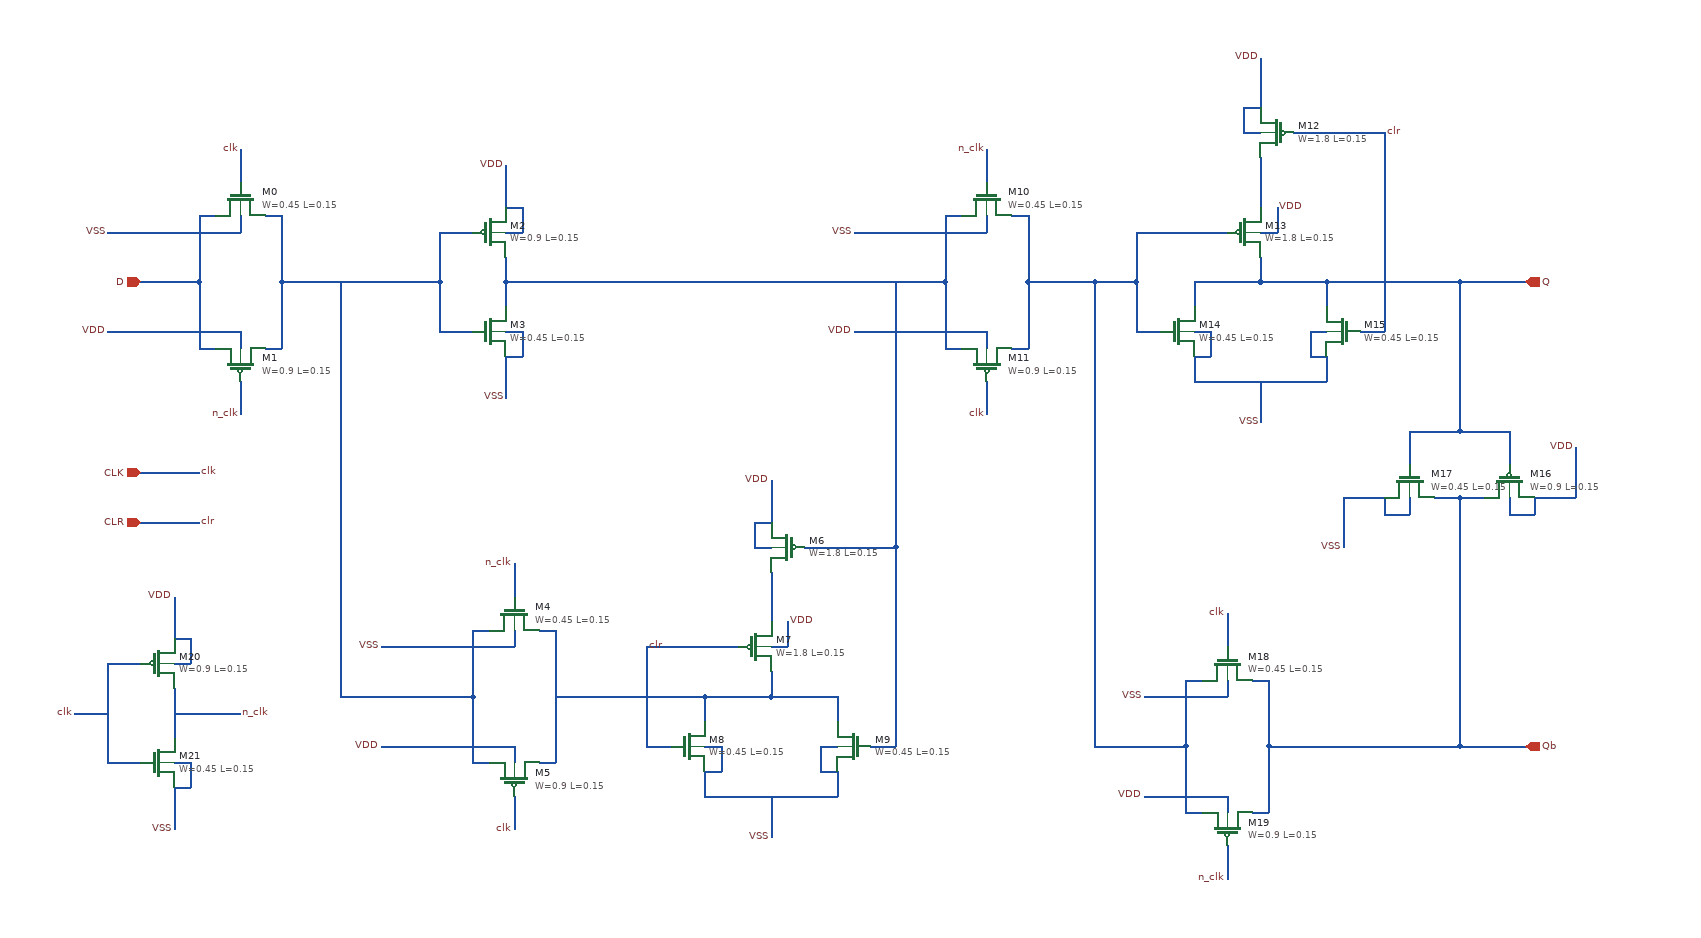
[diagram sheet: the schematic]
v {xschem version=2.9.9 file_version=1.2 }
G {}
K {}
V {}
S {}
E {}
N -3450 -1260 -3420 -1260 { lab=VDD}
N -3420 -1260 -3420 -1240 { lab=VDD}
N -3420 -1400 -3420 -1380 { lab=VSS}
N -3450 -1380 -3420 -1380 { lab=VSS}
N -3420 -1200 -3420 -1160 { lab=n_clk}
N -3420 -1480 -3420 -1440 { lab=clk}
N -3470 -1400 -3450 -1400 { lab=D}
N -3470 -1320 -3470 -1240 { lab=D}
N -3470 -1240 -3450 -1240 { lab=D}
N -3390 -1240 -3370 -1240 { lab=#net1}
N -3370 -1320 -3370 -1240 { lab=#net1}
N -3390 -1400 -3370 -1400 { lab=#net1}
N -3540 -1320 -3470 -1320 { lab=D}
N -3180 -1380 -3140 -1380 { lab=#net1}
N -3180 -1320 -3180 -1260 { lab=#net1}
N -3180 -1260 -3140 -1260 { lab=#net1}
N -3100 -1260 -3080 -1260 { lab=VSS}
N -3080 -1260 -3080 -1230 { lab=VSS}
N -3100 -1230 -3080 -1230 { lab=VSS}
N -3100 -1410 -3080 -1410 { lab=VDD}
N -3080 -1410 -3080 -1380 { lab=VDD}
N -3100 -1380 -3080 -1380 { lab=VDD}
N -3100 -1230 -3100 -1180 { lab=VSS}
N -3100 -1460 -3100 -1410 { lab=VDD}
N -3100 -1320 -3100 -1290 { lab=#net2}
N -3120 -760 -3090 -760 { lab=VDD}
N -3090 -760 -3090 -740 { lab=VDD}
N -3090 -900 -3090 -880 { lab=VSS}
N -3120 -880 -3090 -880 { lab=VSS}
N -3090 -700 -3090 -660 { lab=clk}
N -3090 -980 -3090 -940 { lab=n_clk}
N -3140 -900 -3120 -900 { lab=#net1}
N -3140 -820 -3140 -740 { lab=#net1}
N -3140 -740 -3120 -740 { lab=#net1}
N -3060 -740 -3040 -740 { lab=#net3}
N -3040 -900 -3040 -740 { lab=#net3}
N -3060 -900 -3040 -900 { lab=#net3}
N -3210 -820 -3140 -820 { lab=#net1}
N -2780 -970 -2780 -910 { lab=#net4}
N -2800 -1030 -2780 -1030 { lab=VDD}
N -2800 -1030 -2800 -1000 { lab=VDD}
N -2800 -1000 -2780 -1000 { lab=VDD}
N -2780 -880 -2760 -880 { lab=VDD}
N -2760 -910 -2760 -880 { lab=VDD}
N -2860 -760 -2840 -760 { lab=VSS}
N -2840 -760 -2840 -730 { lab=VSS}
N -2860 -730 -2840 -730 { lab=VSS}
N -2720 -760 -2700 -760 { lab=VSS}
N -2720 -760 -2720 -730 { lab=VSS}
N -2720 -730 -2700 -730 { lab=VSS}
N -2860 -730 -2860 -700 { lab=VSS}
N -2860 -700 -2700 -700 { lab=VSS}
N -2700 -730 -2700 -700 { lab=VSS}
N -2860 -820 -2860 -790 { lab=#net3}
N -2780 -820 -2700 -820 { lab=#net3}
N -2700 -820 -2700 -790 { lab=#net3}
N -2780 -850 -2780 -820 { lab=#net3}
N -2930 -760 -2900 -760 { lab=clr}
N -2930 -880 -2930 -760 { lab=clr}
N -2930 -880 -2820 -880 { lab=clr}
N -2660 -760 -2630 -760 { lab=#net2}
N -2630 -1000 -2630 -760 { lab=#net2}
N -2740 -1000 -2630 -1000 { lab=#net2}
N -2550 -1260 -2520 -1260 { lab=VDD}
N -2520 -1260 -2520 -1240 { lab=VDD}
N -2520 -1400 -2520 -1380 { lab=VSS}
N -2550 -1380 -2520 -1380 { lab=VSS}
N -2520 -1200 -2520 -1160 { lab=clk}
N -2520 -1480 -2520 -1440 { lab=n_clk}
N -2570 -1400 -2550 -1400 { lab=#net2}
N -2570 -1320 -2570 -1240 { lab=#net2}
N -2570 -1240 -2550 -1240 { lab=#net2}
N -2490 -1240 -2470 -1240 { lab=#net5}
N -2470 -1320 -2470 -1240 { lab=#net5}
N -2490 -1400 -2470 -1400 { lab=#net5}
N -2190 -1470 -2190 -1410 { lab=#net6}
N -2210 -1530 -2190 -1530 { lab=VDD}
N -2210 -1530 -2210 -1500 { lab=VDD}
N -2210 -1500 -2190 -1500 { lab=VDD}
N -2190 -1380 -2170 -1380 { lab=VDD}
N -2170 -1410 -2170 -1380 { lab=VDD}
N -2270 -1260 -2250 -1260 { lab=VSS}
N -2250 -1260 -2250 -1230 { lab=VSS}
N -2270 -1230 -2250 -1230 { lab=VSS}
N -2130 -1260 -2110 -1260 { lab=VSS}
N -2130 -1260 -2130 -1230 { lab=VSS}
N -2130 -1230 -2110 -1230 { lab=VSS}
N -2270 -1230 -2270 -1200 { lab=VSS}
N -2270 -1200 -2110 -1200 { lab=VSS}
N -2110 -1230 -2110 -1200 { lab=VSS}
N -2270 -1320 -2270 -1290 { lab=Q}
N -2190 -1320 -2110 -1320 { lab=Q}
N -2110 -1320 -2110 -1290 { lab=Q}
N -2190 -1350 -2190 -1320 { lab=Q}
N -2340 -1260 -2310 -1260 { lab=#net5}
N -2340 -1320 -2340 -1260 { lab=#net5}
N -2340 -1380 -2230 -1380 { lab=#net5}
N -2070 -1260 -2040 -1260 { lab=clr}
N -2040 -1500 -2040 -1260 { lab=clr}
N -2150 -1500 -2040 -1500 { lab=clr}
N -1890 -1140 -1890 -1100 { lab=Q}
N -1950 -1140 -1890 -1140 { lab=Q}
N -2010 -1140 -2010 -1100 { lab=Q}
N -2010 -1060 -2010 -1040 { lab=VSS}
N -2040 -1040 -2010 -1040 { lab=VSS}
N -2040 -1060 -2040 -1040 { lab=VSS}
N -1860 -1060 -1860 -1040 { lab=VDD}
N -1890 -1040 -1860 -1040 { lab=VDD}
N -1890 -1060 -1890 -1040 { lab=VDD}
N -2090 -1060 -2040 -1060 { lab=VSS}
N -1860 -1060 -1810 -1060 { lab=VDD}
N -1950 -1060 -1920 -1060 { lab=Qb}
N -2260 -700 -2230 -700 { lab=VDD}
N -2230 -700 -2230 -680 { lab=VDD}
N -2230 -840 -2230 -820 { lab=VSS}
N -2260 -820 -2230 -820 { lab=VSS}
N -2230 -640 -2230 -600 { lab=n_clk}
N -2230 -920 -2230 -880 { lab=clk}
N -2280 -840 -2260 -840 { lab=#net5}
N -2280 -760 -2280 -680 { lab=#net5}
N -2280 -680 -2260 -680 { lab=#net5}
N -2200 -680 -2180 -680 { lab=Qb}
N -2180 -760 -2180 -680 { lab=Qb}
N -2200 -840 -2180 -840 { lab=Qb}
N -3580 -860 -3540 -860 { lab=clk}
N -3580 -860 -3580 -740 { lab=clk}
N -3580 -740 -3540 -740 { lab=clk}
N -3500 -740 -3480 -740 { lab=VSS}
N -3480 -740 -3480 -710 { lab=VSS}
N -3500 -710 -3480 -710 { lab=VSS}
N -3500 -890 -3480 -890 { lab=VDD}
N -3480 -890 -3480 -860 { lab=VDD}
N -3500 -860 -3480 -860 { lab=VDD}
N -3500 -710 -3500 -660 { lab=VSS}
N -3500 -940 -3500 -890 { lab=VDD}
N -3500 -830 -3500 -770 { lab=n_clk}
N -3370 -1320 -3180 -1320 { lab=#net1}
N -3100 -1320 -2570 -1320 { lab=#net2}
N -2390 -1320 -2340 -1320 { lab=#net5}
N -2110 -1320 -1950 -1320 { lab=Q}
N -1950 -1320 -1950 -1140 { lab=Q}
N -2180 -760 -1950 -760 { lab=Qb}
N -1950 -1060 -1950 -760 { lab=Qb}
N -2390 -1320 -2390 -760 { lab=#net5}
N -3470 -1400 -3470 -1320 { lab=D}
N -3140 -900 -3140 -820 { lab=#net1}
N -2860 -820 -2780 -820 { lab=#net3}
N -2570 -1400 -2570 -1320 { lab=#net2}
N -2270 -1320 -2190 -1320 { lab=Q}
N -2390 -760 -2280 -760 { lab=#net5}
N -2280 -840 -2280 -760 { lab=#net5}
N -3370 -1400 -3370 -1320 { lab=#net1}
N -3180 -1380 -3180 -1320 { lab=#net1}
N -3100 -1350 -3100 -1320 { lab=#net2}
N -2470 -1400 -2470 -1320 { lab=#net5}
N -2340 -1380 -2340 -1320 { lab=#net5}
N -2010 -1140 -1950 -1140 { lab=Q}
N -2180 -840 -2180 -760 { lab=Qb}
N -1980 -1060 -1950 -1060 { lab=Qb}
N -2470 -1320 -2390 -1320 { lab=#net5}
N -2630 -1320 -2630 -1000 { lab=#net2}
N -3040 -820 -2860 -820 { lab=#net3}
N -3300 -1320 -3300 -820 { lab=#net1}
N -3300 -820 -3210 -820 { lab=#net1}
N -1950 -1320 -1870 -1320 { lab=Q}
N -1950 -760 -1870 -760 { lab=Qb}
N -3540 -1090 -3470 -1090 { lab=clk}
N -3540 -1030 -3470 -1030 { lab=clr}
N -3620 -800 -3580 -800 { lab=clk}
N -3500 -800 -3420 -800 { lab=n_clk}
N -1810 -1120 -1810 -1060 { lab=VDD}
N -2090 -1060 -2090 -1000 { lab=VSS}
N -2780 -700 -2780 -650 { lab=VSS}
N -2190 -1200 -2190 -1150 { lab=VSS}
N -2190 -1590 -2190 -1530 { lab=VDD}
N -2780 -1080 -2780 -1030 { lab=VDD}
N -2330 -700 -2260 -700 { lab=VDD}
N -2330 -820 -2260 -820 { lab=VSS}
N -2680 -1380 -2550 -1380 { lab=VSS}
N -2680 -1260 -2550 -1260 { lab=VDD}
N -3250 -880 -3120 -880 { lab=VSS}
N -3250 -760 -3120 -760 { lab=VDD}
N -3580 -1380 -3450 -1380 { lab=VSS}
N -3580 -1260 -3450 -1260 { lab=VDD}
C {sky130_fd_pr/nfet_01v8.sym} -3420 -1420 1 0 {name=M0
L=0.15
W=0.45
nf=1 
mult=1
ad="'int((nf+1)/2) * W/nf * 0.29'" 
pd="'2*int((nf+1)/2) * (W/nf + 0.29)'"
as="'int((nf+2)/2) * W/nf * 0.29'" 
ps="'2*int((nf+2)/2) * (W/nf + 0.29)'"
nrd="'0.29 / W'" nrs="'0.29 / W'"
sa=0 sb=0 sd=0
model=nfet_01v8
spiceprefix=X
}
C {sky130_fd_pr/pfet_01v8.sym} -3420 -1220 3 0 {name=M1
L=0.15
W=0.9
nf=1
mult=1
ad="'int((nf+1)/2) * W/nf * 0.29'" 
pd="'2*int((nf+1)/2) * (W/nf + 0.29)'"
as="'int((nf+2)/2) * W/nf * 0.29'" 
ps="'2*int((nf+2)/2) * (W/nf + 0.29)'"
nrd="'0.29 / W'" nrs="'0.29 / W'"
sa=0 sb=0 sd=0
model=pfet_01v8
spiceprefix=X
}
C {sky130_fd_pr/pfet_01v8.sym} -3120 -1380 0 0 {name=M2
L=0.15
W=0.9
nf=1
mult=1
ad="'int((nf+1)/2) * W/nf * 0.29'" 
pd="'2*int((nf+1)/2) * (W/nf + 0.29)'"
as="'int((nf+2)/2) * W/nf * 0.29'" 
ps="'2*int((nf+2)/2) * (W/nf + 0.29)'"
nrd="'0.29 / W'" nrs="'0.29 / W'"
sa=0 sb=0 sd=0
model=pfet_01v8
spiceprefix=X
}
C {sky130_fd_pr/nfet_01v8.sym} -3120 -1260 0 0 {name=M3
L=0.15
W=0.45
nf=1 
mult=1
ad="'int((nf+1)/2) * W/nf * 0.29'" 
pd="'2*int((nf+1)/2) * (W/nf + 0.29)'"
as="'int((nf+2)/2) * W/nf * 0.29'" 
ps="'2*int((nf+2)/2) * (W/nf + 0.29)'"
nrd="'0.29 / W'" nrs="'0.29 / W'"
sa=0 sb=0 sd=0
model=nfet_01v8
spiceprefix=X
}
C {sky130_fd_pr/nfet_01v8.sym} -3090 -920 1 0 {name=M4
L=0.15
W=0.45
nf=1 
mult=1
ad="'int((nf+1)/2) * W/nf * 0.29'" 
pd="'2*int((nf+1)/2) * (W/nf + 0.29)'"
as="'int((nf+2)/2) * W/nf * 0.29'" 
ps="'2*int((nf+2)/2) * (W/nf + 0.29)'"
nrd="'0.29 / W'" nrs="'0.29 / W'"
sa=0 sb=0 sd=0
model=nfet_01v8
spiceprefix=X
}
C {sky130_fd_pr/pfet_01v8.sym} -3090 -720 3 0 {name=M5
L=0.15
W=0.9
nf=1
mult=1
ad="'int((nf+1)/2) * W/nf * 0.29'" 
pd="'2*int((nf+1)/2) * (W/nf + 0.29)'"
as="'int((nf+2)/2) * W/nf * 0.29'" 
ps="'2*int((nf+2)/2) * (W/nf + 0.29)'"
nrd="'0.29 / W'" nrs="'0.29 / W'"
sa=0 sb=0 sd=0
model=pfet_01v8
spiceprefix=X
}
C {sky130_fd_pr/pfet_01v8.sym} -2760 -1000 0 1 {name=M6
L=0.15
W=1.8
nf=1
mult=1
ad="'int((nf+1)/2) * W/nf * 0.29'" 
pd="'2*int((nf+1)/2) * (W/nf + 0.29)'"
as="'int((nf+2)/2) * W/nf * 0.29'" 
ps="'2*int((nf+2)/2) * (W/nf + 0.29)'"
nrd="'0.29 / W'" nrs="'0.29 / W'"
sa=0 sb=0 sd=0
model=pfet_01v8
spiceprefix=X
}
C {sky130_fd_pr/pfet_01v8.sym} -2800 -880 0 0 {name=M7
L=0.15
W=1.8
nf=1
mult=1
ad="'int((nf+1)/2) * W/nf * 0.29'" 
pd="'2*int((nf+1)/2) * (W/nf + 0.29)'"
as="'int((nf+2)/2) * W/nf * 0.29'" 
ps="'2*int((nf+2)/2) * (W/nf + 0.29)'"
nrd="'0.29 / W'" nrs="'0.29 / W'"
sa=0 sb=0 sd=0
model=pfet_01v8
spiceprefix=X
}
C {sky130_fd_pr/nfet_01v8.sym} -2880 -760 0 0 {name=M8
L=0.15
W=0.45
nf=1 
mult=1
ad="'int((nf+1)/2) * W/nf * 0.29'" 
pd="'2*int((nf+1)/2) * (W/nf + 0.29)'"
as="'int((nf+2)/2) * W/nf * 0.29'" 
ps="'2*int((nf+2)/2) * (W/nf + 0.29)'"
nrd="'0.29 / W'" nrs="'0.29 / W'"
sa=0 sb=0 sd=0
model=nfet_01v8
spiceprefix=X
}
C {sky130_fd_pr/nfet_01v8.sym} -2680 -760 0 1 {name=M9
L=0.15
W=0.45
nf=1 
mult=1
ad="'int((nf+1)/2) * W/nf * 0.29'" 
pd="'2*int((nf+1)/2) * (W/nf + 0.29)'"
as="'int((nf+2)/2) * W/nf * 0.29'" 
ps="'2*int((nf+2)/2) * (W/nf + 0.29)'"
nrd="'0.29 / W'" nrs="'0.29 / W'"
sa=0 sb=0 sd=0
model=nfet_01v8
spiceprefix=X
}
C {sky130_fd_pr/nfet_01v8.sym} -2520 -1420 1 0 {name=M10
L=0.15
W=0.45
nf=1 
mult=1
ad="'int((nf+1)/2) * W/nf * 0.29'" 
pd="'2*int((nf+1)/2) * (W/nf + 0.29)'"
as="'int((nf+2)/2) * W/nf * 0.29'" 
ps="'2*int((nf+2)/2) * (W/nf + 0.29)'"
nrd="'0.29 / W'" nrs="'0.29 / W'"
sa=0 sb=0 sd=0
model=nfet_01v8
spiceprefix=X
}
C {sky130_fd_pr/pfet_01v8.sym} -2520 -1220 3 0 {name=M11
L=0.15
W=0.9
nf=1
mult=1
ad="'int((nf+1)/2) * W/nf * 0.29'" 
pd="'2*int((nf+1)/2) * (W/nf + 0.29)'"
as="'int((nf+2)/2) * W/nf * 0.29'" 
ps="'2*int((nf+2)/2) * (W/nf + 0.29)'"
nrd="'0.29 / W'" nrs="'0.29 / W'"
sa=0 sb=0 sd=0
model=pfet_01v8
spiceprefix=X
}
C {sky130_fd_pr/pfet_01v8.sym} -2170 -1500 0 1 {name=M12
L=0.15
W=1.8
nf=1
mult=1
ad="'int((nf+1)/2) * W/nf * 0.29'" 
pd="'2*int((nf+1)/2) * (W/nf + 0.29)'"
as="'int((nf+2)/2) * W/nf * 0.29'" 
ps="'2*int((nf+2)/2) * (W/nf + 0.29)'"
nrd="'0.29 / W'" nrs="'0.29 / W'"
sa=0 sb=0 sd=0
model=pfet_01v8
spiceprefix=X
}
C {sky130_fd_pr/pfet_01v8.sym} -2210 -1380 0 0 {name=M13
L=0.15
W=1.8
nf=1
mult=1
ad="'int((nf+1)/2) * W/nf * 0.29'" 
pd="'2*int((nf+1)/2) * (W/nf + 0.29)'"
as="'int((nf+2)/2) * W/nf * 0.29'" 
ps="'2*int((nf+2)/2) * (W/nf + 0.29)'"
nrd="'0.29 / W'" nrs="'0.29 / W'"
sa=0 sb=0 sd=0
model=pfet_01v8
spiceprefix=X
}
C {sky130_fd_pr/nfet_01v8.sym} -2290 -1260 0 0 {name=M14
L=0.15
W=0.45
nf=1 
mult=1
ad="'int((nf+1)/2) * W/nf * 0.29'" 
pd="'2*int((nf+1)/2) * (W/nf + 0.29)'"
as="'int((nf+2)/2) * W/nf * 0.29'" 
ps="'2*int((nf+2)/2) * (W/nf + 0.29)'"
nrd="'0.29 / W'" nrs="'0.29 / W'"
sa=0 sb=0 sd=0
model=nfet_01v8
spiceprefix=X
}
C {sky130_fd_pr/nfet_01v8.sym} -2090 -1260 0 1 {name=M15
L=0.15
W=0.45
nf=1 
mult=1
ad="'int((nf+1)/2) * W/nf * 0.29'" 
pd="'2*int((nf+1)/2) * (W/nf + 0.29)'"
as="'int((nf+2)/2) * W/nf * 0.29'" 
ps="'2*int((nf+2)/2) * (W/nf + 0.29)'"
nrd="'0.29 / W'" nrs="'0.29 / W'"
sa=0 sb=0 sd=0
model=nfet_01v8
spiceprefix=X
}
C {sky130_fd_pr/pfet_01v8.sym} -1890 -1080 1 0 {name=M16
L=0.15
W=0.9
nf=1
mult=1
ad="'int((nf+1)/2) * W/nf * 0.29'" 
pd="'2*int((nf+1)/2) * (W/nf + 0.29)'"
as="'int((nf+2)/2) * W/nf * 0.29'" 
ps="'2*int((nf+2)/2) * (W/nf + 0.29)'"
nrd="'0.29 / W'" nrs="'0.29 / W'"
sa=0 sb=0 sd=0
model=pfet_01v8
spiceprefix=X
}
C {sky130_fd_pr/nfet_01v8.sym} -2010 -1080 1 0 {name=M17
L=0.15
W=0.45
nf=1 
mult=1
ad="'int((nf+1)/2) * W/nf * 0.29'" 
pd="'2*int((nf+1)/2) * (W/nf + 0.29)'"
as="'int((nf+2)/2) * W/nf * 0.29'" 
ps="'2*int((nf+2)/2) * (W/nf + 0.29)'"
nrd="'0.29 / W'" nrs="'0.29 / W'"
sa=0 sb=0 sd=0
model=nfet_01v8
spiceprefix=X
}
C {sky130_fd_pr/nfet_01v8.sym} -2230 -860 1 0 {name=M18
L=0.15
W=0.45
nf=1 
mult=1
ad="'int((nf+1)/2) * W/nf * 0.29'" 
pd="'2*int((nf+1)/2) * (W/nf + 0.29)'"
as="'int((nf+2)/2) * W/nf * 0.29'" 
ps="'2*int((nf+2)/2) * (W/nf + 0.29)'"
nrd="'0.29 / W'" nrs="'0.29 / W'"
sa=0 sb=0 sd=0
model=nfet_01v8
spiceprefix=X
}
C {sky130_fd_pr/pfet_01v8.sym} -2230 -660 3 0 {name=M19
L=0.15
W=0.9
nf=1
mult=1
ad="'int((nf+1)/2) * W/nf * 0.29'" 
pd="'2*int((nf+1)/2) * (W/nf + 0.29)'"
as="'int((nf+2)/2) * W/nf * 0.29'" 
ps="'2*int((nf+2)/2) * (W/nf + 0.29)'"
nrd="'0.29 / W'" nrs="'0.29 / W'"
sa=0 sb=0 sd=0
model=pfet_01v8
spiceprefix=X
}
C {sky130_fd_pr/pfet_01v8.sym} -3520 -860 0 0 {name=M20
L=0.15
W=0.9
nf=1
mult=1
ad="'int((nf+1)/2) * W/nf * 0.29'" 
pd="'2*int((nf+1)/2) * (W/nf + 0.29)'"
as="'int((nf+2)/2) * W/nf * 0.29'" 
ps="'2*int((nf+2)/2) * (W/nf + 0.29)'"
nrd="'0.29 / W'" nrs="'0.29 / W'"
sa=0 sb=0 sd=0
model=pfet_01v8
spiceprefix=X
}
C {sky130_fd_pr/nfet_01v8.sym} -3520 -740 0 0 {name=M21
L=0.15
W=0.45
nf=1 
mult=1
ad="'int((nf+1)/2) * W/nf * 0.29'" 
pd="'2*int((nf+1)/2) * (W/nf + 0.29)'"
as="'int((nf+2)/2) * W/nf * 0.29'" 
ps="'2*int((nf+2)/2) * (W/nf + 0.29)'"
nrd="'0.29 / W'" nrs="'0.29 / W'"
sa=0 sb=0 sd=0
model=nfet_01v8
spiceprefix=X
}
C {ipin.sym} -3540 -1320 0 0 {name=p1 lab=D}
C {opin.sym} -1870 -1320 0 0 {name=p2 lab=Q}
C {opin.sym} -1870 -760 0 0 {name=p3 lab=Qb}
C {ipin.sym} -3540 -1090 0 0 {name=p4 lab=CLK}
C {ipin.sym} -3540 -1030 0 0 {name=p5 lab=CLR}
C {lab_wire.sym} -3470 -1090 0 1 {name=l1 sig_type=std_logic lab=clk}
C {lab_wire.sym} -3470 -1030 0 1 {name=l2 sig_type=std_logic lab=clr}
C {lab_wire.sym} -3620 -800 0 0 {name=l3 sig_type=std_logic lab=clk}
C {lab_wire.sym} -3420 -800 0 1 {name=l4 sig_type=std_logic lab=n_clk}
C {lab_wire.sym} -3420 -1480 0 0 {name=l5 sig_type=std_logic lab=clk}
C {lab_wire.sym} -2520 -1160 2 1 {name=l6 sig_type=std_logic lab=clk}
C {lab_wire.sym} -3090 -660 2 1 {name=l7 sig_type=std_logic lab=clk}
C {lab_wire.sym} -2230 -920 0 0 {name=l8 sig_type=std_logic lab=clk}
C {lab_wire.sym} -3420 -1160 2 1 {name=l9 sig_type=std_logic lab=n_clk}
C {lab_wire.sym} -2230 -600 2 1 {name=l10 sig_type=std_logic lab=n_clk}
C {lab_wire.sym} -2520 -1480 0 0 {name=l11 sig_type=std_logic lab=n_clk}
C {lab_wire.sym} -3090 -980 0 0 {name=l12 sig_type=std_logic lab=n_clk}
C {lab_wire.sym} -3100 -1460 0 0 {name=l13 sig_type=std_logic lab=VDD}
C {lab_wire.sym} -3100 -1180 2 1 {name=l14 sig_type=std_logic lab=VSS}
C {lab_wire.sym} -1810 -1120 0 0 {name=l15 sig_type=std_logic lab=VDD}
C {lab_wire.sym} -2090 -1000 2 1 {name=l16 sig_type=std_logic lab=VSS}
C {lab_wire.sym} -2780 -650 2 1 {name=l17 sig_type=std_logic lab=VSS}
C {lab_wire.sym} -2190 -1150 2 1 {name=l18 sig_type=std_logic lab=VSS}
C {lab_wire.sym} -2190 -1590 0 0 {name=l19 sig_type=std_logic lab=VDD}
C {lab_wire.sym} -2780 -1080 0 0 {name=l20 sig_type=std_logic lab=VDD}
C {lab_wire.sym} -3500 -940 0 0 {name=l21 sig_type=std_logic lab=VDD}
C {lab_wire.sym} -3500 -660 2 1 {name=l22 sig_type=std_logic lab=VSS}
C {lab_wire.sym} -2040 -1500 0 1 {name=l23 sig_type=std_logic lab=clr}
C {lab_wire.sym} -2930 -880 0 1 {name=l24 sig_type=std_logic lab=clr}
C {lab_wire.sym} -2170 -1410 0 1 {name=l25 sig_type=std_logic lab=VDD}
C {lab_wire.sym} -2760 -910 0 1 {name=l26 sig_type=std_logic lab=VDD}
C {lab_wire.sym} -2330 -700 0 0 {name=l27 sig_type=std_logic lab=VDD}
C {lab_wire.sym} -2330 -820 2 1 {name=l28 sig_type=std_logic lab=VSS}
C {lab_wire.sym} -2680 -1260 0 0 {name=l29 sig_type=std_logic lab=VDD}
C {lab_wire.sym} -2680 -1380 2 1 {name=l30 sig_type=std_logic lab=VSS}
C {lab_wire.sym} -3250 -760 0 0 {name=l31 sig_type=std_logic lab=VDD}
C {lab_wire.sym} -3250 -880 2 1 {name=l32 sig_type=std_logic lab=VSS}
C {lab_wire.sym} -3580 -1260 0 0 {name=l33 sig_type=std_logic lab=VDD}
C {lab_wire.sym} -3580 -1380 2 1 {name=l34 sig_type=std_logic lab=VSS}
